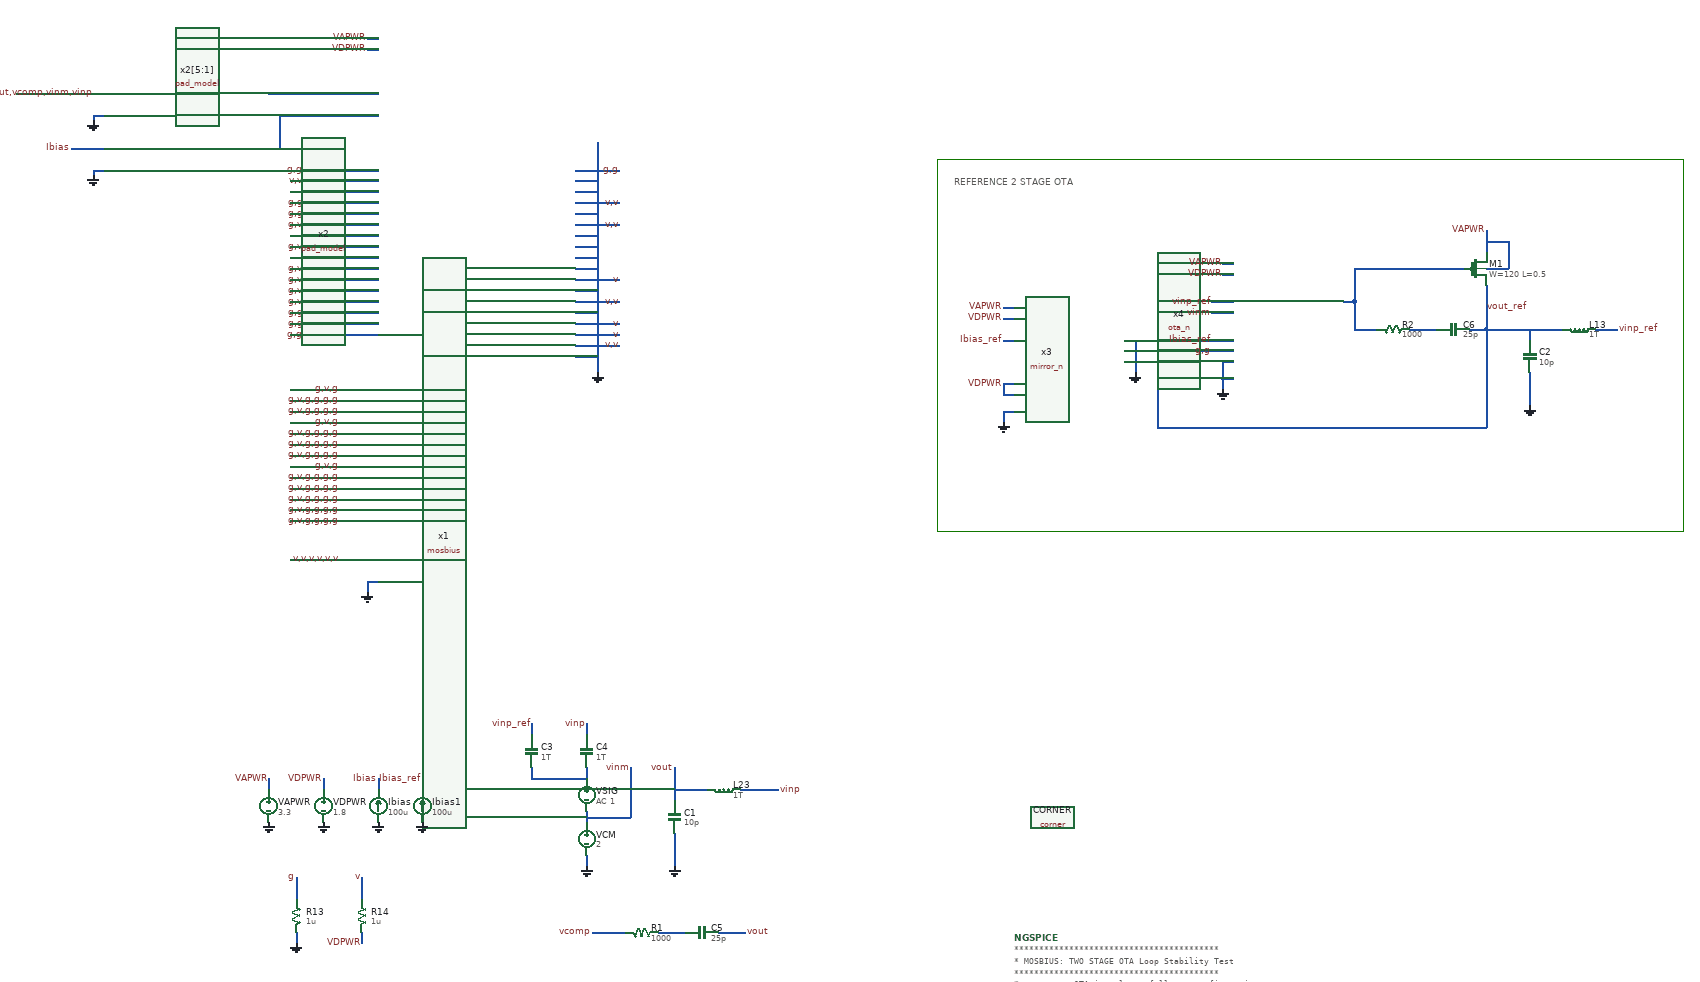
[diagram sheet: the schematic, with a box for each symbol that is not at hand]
v {xschem version=3.1.0 file_version=1.2
}
G {}
K {}
V {}
S {}
E {}
L 4 1320 -1030 1320 -350 {}
L 4 2680 -1030 2680 -350 {}
L 4 1320 -1030 2680 -1030 {}
L 4 1320 -350 2680 -350 {}
T {REFERENCE 2 STAGE OTA} 1350 -1000 0 0 0.4 0.4 {}
N 100 100 100 120 {
lab=VAPWR}
N 200 100 200 120 {
lab=VDPWR}
N 280 -1230 300 -1230 {
lab=VDPWR}
N 280 -1250 300 -1250 {
lab=VAPWR}
N 280 -260 280 -240 {
lab=GND}
N 280 -260 300 -260 {
lab=GND}
N 300 100 300 120 {
lab=Ibias}
N 660 -890 700 -890 {
lab=GND}
N 660 -870 700 -870 {
lab=GND}
N 660 -850 700 -850 {
lab=GND}
N 660 -830 700 -830 {
lab=GND}
N 680 240 680 260 {
lab=GND}
N 680 160 680 180 {
lab=vinm}
N 680 80 680 100 {
lab=#net1}
N 840 80 840 140 {
lab=vout}
N 840 200 840 260 {
lab=GND}
N 680 170 760 170 {
lab=vinm}
N 760 80 760 170 {
lab=vinm}
N 840 120 900 120 {
lab=vout}
N 960 120 1000 120 {
lab=vinp}
N 660 -1010 740 -1010 {
lab=g,g}
N 660 -990 700 -990 {
lab=GND}
N 150 380 150 400 {
lab=GND}
N 150 280 150 320 {
lab=g}
N 270 280 270 320 {
lab=v}
N 270 380 270 400 {
lab=VDPWR}
N 140 -370 300 -370 {
lab=g,v,g,g,g,g}
N 140 -390 300 -390 {
lab=g,v,g,g,g,g}
N 140 -410 300 -410 {
lab=g,v,g,g,g,g}
N 140 -430 300 -430 {
lab=g,v,g,g,g,g}
N 140 -450 300 -450 {
lab=g,v,g,g,g,g}
N 140 -470 300 -470 {
lab=g,v,g}
N 140 -490 300 -490 {
lab=g,v,g,g,g,g}
N 140 -510 300 -510 {
lab=g,v,g,g,g,g}
N 140 -530 300 -530 {
lab=g,v,g,g,g,g}
N 140 -550 300 -550 {
lab=g,v,g}
N 140 -570 300 -570 {
lab=g,v,g,g,g,g}
N 140 -590 300 -590 {
lab=g,v,g,g,g,g}
N 140 -610 300 -610 {
lab=g,v,g}
N 140 -710 300 -710 {
lab=g,g,g,g,g,g}
N 140 -730 300 -730 {
lab=g,g,g,v,g,g}
N 140 -750 300 -750 {
lab=g,g,v,g,g,g}
N 140 -770 300 -770 {
lab=g,v,g,g,g,g}
N 140 -790 300 -790 {
lab=g,v,g,g,g,g}
N 140 -810 300 -810 {
lab=g,v,g,g,g,g}
N 140 -830 300 -830 {
lab=g,v,g,g,g,g}
N 140 -870 300 -870 {
lab=g,v,g,g,g,g}
N 140 -910 300 -910 {
lab=g,v,g,g,g,g}
N 140 -930 300 -930 {
lab=g,g,v,g,g,g}
N 140 -1010 300 -1010 {
lab=g,g,g,g,g,g}
N 140 -850 300 -850 {
lab=g,g,v}
N 140 -890 300 -890 {
lab=g,g,v}
N 140 -300 300 -300 {
lab=v,v,v,v,v,v}
N 140 -990 300 -990 {
lab=v,v,g,g,g,g}
N 140 -970 300 -970 {
lab=g,g,v}
N 140 -950 300 -950 {
lab=g,g,g,v,g,g}
N 1840 -820 1860 -820 {
lab=VDPWR}
N 1840 -840 1860 -840 {
lab=VAPWR}
N 1840 -630 1840 -610 {
lab=GND}
N 1840 -630 1860 -630 {
lab=GND}
N 1440 -740 1460 -740 {
lab=VDPWR}
N 1440 -760 1460 -760 {
lab=VAPWR}
N 1440 -570 1440 -550 {
lab=GND}
N 1440 -570 1460 -570 {
lab=GND}
N 1440 -600 1460 -600 {
lab=VDPWR}
N 1440 -620 1460 -620 {
lab=VDPWR}
N 1440 -620 1440 -600 {
lab=VDPWR}
N 1660 -660 1680 -660 {
lab=GND}
N 380 100 380 120 {
lab=Ibias_ref}
N 1440 -700 1460 -700 {
lab=Ibias_ref}
N 1840 -660 1860 -660 {
lab=GND}
N 1840 -660 1840 -630 {
lab=GND}
N 1800 -680 1860 -680 {
lab=g,g}
N 1820 -770 1860 -770 {
lab=vinp_ref}
N 1820 -750 1860 -750 {
lab=vinm}
N 2400 -640 2400 -580 {
lab=GND}
N 2520 -720 2560 -720 {
lab=vinp_ref}
N 1800 -700 1860 -700 {
lab=Ibias_ref}
N -360 -1150 -200 -1150 {
lab=g,vout,vcomp,vinm,vinp}
N 100 -1150 300 -1150 {
lab=#net2}
N -260 -1050 -200 -1050 {
lab=Ibias}
N 100 -1050 120 -1050 {
lab=#net3}
N 120 -1110 120 -1050 {
lab=#net3}
N 120 -1110 300 -1110 {
lab=#net3}
N -220 -1010 -220 -1000 {
lab=GND}
N -220 -1010 -200 -1010 {
lab=GND}
N -220 -1110 -220 -1100 {
lab=GND}
N -220 -1110 -200 -1110 {
lab=GND}
N 1000 120 1030 120 {
lab=vinp}
N 810 380 860 380 {
lab=#net4}
N 920 380 970 380 {
lab=vout}
N 690 380 750 380 {
lab=vcomp}
N 660 -710 740 -710 {
lab=v}
N 680 -0 680 20 {
lab=vinp}
N 1660 -700 1680 -700 {
lab=GND}
N 700 -1060 700 -640 {
lab=GND}
N 660 -910 740 -910 {
lab=v,v}
N 660 -950 740 -950 {
lab=v,v}
N 660 -970 700 -970 {
lab=GND}
N 660 -930 700 -930 {
lab=GND}
N 660 -810 740 -810 {
lab=v}
N 660 -790 700 -790 {
lab=GND}
N 660 -730 740 -730 {
lab=v}
N 660 -690 740 -690 {
lab=v,v}
N 660 -770 740 -770 {
lab=v,v}
N 660 -750 700 -750 {
lab=GND}
N 660 -670 700 -670 {
lab=GND}
N 2240 -830 2280 -830 {
lab=#net5}
N 1680 -700 1680 -640 {
lab=GND}
N 1660 -680 1720 -680 {
lab=vout_ref}
N 1720 -680 1720 -540 {
lab=vout_ref}
N 1720 -540 2220 -540 {
lab=vout_ref}
N 2320 -900 2320 -860 {
lab=VAPWR}
N 2320 -830 2360 -830 {
lab=VAPWR}
N 2360 -880 2360 -830 {
lab=VAPWR}
N 2320 -880 2360 -880 {
lab=VAPWR}
N 2400 -720 2400 -700 {
lab=vout_ref}
N 580 100 680 100 {
lab=#net1}
N 580 80 580 100 {
lab=#net1}
N 580 0 580 20 {
lab=vinp_ref}
N 2180 -720 2230 -720 {
lab=#net6}
N 2320 -800 2320 -720 {
lab=vout_ref}
N 2320 -720 2460 -720 {
lab=vout_ref}
N 2060 -770 2080 -770 {
lab=#net5}
N 2080 -830 2080 -770 {
lab=#net5}
N 2080 -830 2240 -830 {
lab=#net5}
N 2220 -540 2320 -540 {
lab=vout_ref}
N 2320 -720 2320 -540 {
lab=vout_ref}
N 2290 -720 2320 -720 {
lab=vout_ref}
N 2080 -720 2120 -720 {
lab=#net5}
N 2080 -770 2080 -720 {
lab=#net5}
C {mosbius.sym} 300 -240 0 0 {name=x1}
C {devices/vsource.sym} 100 150 0 0 {name=VAPWR value=3.3}
C {devices/gnd.sym} 100 180 0 0 {name=l1 lab=GND}
C {devices/lab_pin.sym} 100 100 1 0 {name=p2 sig_type=std_logic lab=VAPWR}
C {devices/vsource.sym} 200 150 0 0 {name=VDPWR value=1.8}
C {devices/gnd.sym} 200 180 0 0 {name=l2 lab=GND}
C {devices/lab_pin.sym} 200 100 1 0 {name=p3 sig_type=std_logic lab=VDPWR}
C {devices/lab_pin.sym} 280 -1250 0 0 {name=p4 sig_type=std_logic lab=VAPWR}
C {devices/lab_pin.sym} 280 -1230 0 0 {name=p5 sig_type=std_logic lab=VDPWR}
C {devices/gnd.sym} 280 -240 0 0 {name=l3 lab=GND}
C {devices/isource.sym} 300 150 2 1 {name=Ibias value=100u}
C {devices/gnd.sym} 300 180 0 0 {name=l4 lab=GND}
C {devices/lab_pin.sym} 300 100 1 0 {name=p1 sig_type=std_logic lab=Ibias}
C {devices/gnd.sym} 700 -640 0 0 {name=l5 lab=GND}
C {devices/vsource.sym} 680 130 0 0 {name=VSIG value="AC 1"}
C {devices/vsource.sym} 680 210 0 0 {name=VCM value=2}
C {devices/gnd.sym} 680 260 0 0 {name=l9 lab=GND}
C {devices/lab_pin.sym} 680 0 1 0 {name=p10 sig_type=std_logic lab=vinp}
C {devices/capa.sym} 840 170 0 0 {name=C1
m=1
value=10p
footprint=1206
device="ceramic capacitor"}
C {devices/gnd.sym} 840 260 0 0 {name=l19 lab=GND}
C {devices/lab_pin.sym} 760 80 1 0 {name=p28 sig_type=std_logic lab=vinm}
C {devices/ind.sym} 930 120 1 0 {name=L23
m=1
value=1T
footprint=1206
device=inductor}
C {sky130_fd_pr/corner.sym} 1530 170 0 0 {name=CORNER only_toplevel=true corner=tt}
C {devices/code_shown.sym} 1460 390 0 0 {name=NGSPICE only_toplevel=true value=
"
*****************************************
* MOSBIUS: TWO STAGE OTA Loop Stability Test
*****************************************
* two stage-OTA in voltage follower configuration,
* plots bode plot, and calculates bandwidth and phase margin, 
* compared to reference OTA
*****************************************
* try tuning ctrl_otan_tail[1:0] for variable tail current
*****************************************
* BUS1: OTA INP
* BUS2: OTA INM
* BUS3: OTA Compensation
* BUS4: OTA OUT
* BUS5: GND
* BUS6: GND
*****************************************
.control
   save all
   set temp = 27
   ac dec 51 1k 1G
   let vout_mag = mag(v(vout))                 ; loop gain
   let vout_ref_mag = mag(v(vout_ref))         ; loop gain of reference OTA
   let phase = cph(vout)/PI*180-180            ; phase margin
   let phase_ref = cph(vout_ref)/PI*180-180    ; phase margin of reference OTA
   meas ac f_bw WHEN vout_mag=1                ; calc bandwidth
   meas ac f_bw_ref WHEN vout_ref_mag=1        ; calc bandwidth of reference OTA
   meas ac pm FIND phase AT=f_bw               ; calc phase at ugb
   meas ac pm_ref FIND phase_ref AT=f_bw_ref   ; calc phase at ugb or reference OTA
   plot vdb(vout) vdb(vout_ref)               ; plot loop gain
   plot phase phase_ref
.endc
"}
C {devices/gnd.sym} 150 400 0 0 {name=l10 lab=GND}
C {devices/res.sym} 150 350 0 0 {name=R13
value=1u
footprint=1206
device=resistor
m=1}
C {devices/lab_pin.sym} 150 280 0 0 {name=p17 sig_type=std_logic lab=g}
C {devices/res.sym} 270 350 0 0 {name=R14
value=1u
footprint=1206
device=resistor
m=1}
C {devices/lab_pin.sym} 270 400 3 0 {name=p18 sig_type=std_logic lab=VDPWR}
C {devices/lab_pin.sym} 270 280 0 0 {name=p19 sig_type=std_logic lab=v}
C {devices/lab_wire.sym} 230 -450 0 0 {name=p24 sig_type=std_logic lab=g,v,g,g,g,g}
C {devices/lab_wire.sym} 230 -490 0 0 {name=p39 sig_type=std_logic lab=g,v,g,g,g,g}
C {devices/lab_wire.sym} 230 -510 0 0 {name=p40 sig_type=std_logic lab=g,v,g,g,g,g}
C {devices/lab_wire.sym} 230 -530 0 0 {name=p41 sig_type=std_logic lab=g,v,g,g,g,g}
C {devices/lab_wire.sym} 230 -570 0 0 {name=p43 sig_type=std_logic lab=g,v,g,g,g,g}
C {devices/lab_wire.sym} 230 -590 0 0 {name=p44 sig_type=std_logic lab=g,v,g,g,g,g}
C {devices/lab_wire.sym} 230 -610 0 0 {name=p45 sig_type=std_logic lab=g,v,g}
C {devices/lab_wire.sym} 230 -710 0 0 {name=p46 sig_type=std_logic lab=g,g,g,g,g,g}
C {devices/lab_wire.sym} 230 -730 0 0 {name=p47 sig_type=std_logic lab=g,g,g,v,g,g}
C {devices/lab_wire.sym} 230 -750 0 0 {name=p48 sig_type=std_logic lab=g,g,v,g,g,g}
C {devices/lab_wire.sym} 230 -770 0 0 {name=p49 sig_type=std_logic lab=g,v,g,g,g,g}
C {devices/lab_wire.sym} 230 -790 0 0 {name=p50 sig_type=std_logic lab=g,v,g,g,g,g}
C {devices/lab_wire.sym} 230 -810 0 0 {name=p51 sig_type=std_logic lab=g,v,g,g,g,g}
C {devices/lab_wire.sym} 230 -830 0 0 {name=p52 sig_type=std_logic lab=g,v,g,g,g,g}
C {devices/lab_wire.sym} 230 -870 0 0 {name=p53 sig_type=std_logic lab=g,v,g,g,g,g}
C {devices/lab_wire.sym} 230 -910 0 0 {name=p54 sig_type=std_logic lab=g,v,g,g,g,g}
C {devices/lab_wire.sym} 230 -930 0 0 {name=p55 sig_type=std_logic lab=g,g,v,g,g,g}
C {devices/lab_wire.sym} 230 -1010 0 0 {name=p56 sig_type=std_logic lab=g,g,g,g,g,g}
C {devices/lab_wire.sym} 230 -850 0 0 {name=p57 sig_type=std_logic lab=g,g,v}
C {devices/lab_wire.sym} 230 -890 0 0 {name=p58 sig_type=std_logic lab=g,g,v}
C {devices/lab_wire.sym} 230 -300 0 0 {name=p25 sig_type=std_logic lab=v,v,v,v,v,v}
C {devices/lab_wire.sym} 740 -1010 0 0 {name=p14 sig_type=std_logic lab=g,g}
C {devices/lab_wire.sym} 230 -990 0 0 {name=p11 sig_type=std_logic lab=v,v,g,g,g,g}
C {devices/lab_wire.sym} 230 -970 0 0 {name=p15 sig_type=std_logic lab=g,g,v}
C {devices/lab_wire.sym} 230 -950 0 0 {name=p7 sig_type=std_logic lab=g,g,g,v,g,g}
C {devices/lab_pin.sym} 840 80 1 0 {name=p8 sig_type=std_logic lab=vout}
C {ota_n.sym} 1620 -740 0 0 {name=x4}
C {devices/lab_pin.sym} 1840 -840 0 0 {name=p13 sig_type=std_logic lab=VAPWR}
C {devices/lab_pin.sym} 1840 -820 0 0 {name=p23 sig_type=std_logic lab=VDPWR}
C {devices/gnd.sym} 1840 -610 0 0 {name=l7 lab=GND}
C {mirror_n.sym} 1510 -700 0 0 {name=x3}
C {devices/lab_pin.sym} 1440 -760 0 0 {name=p26 sig_type=std_logic lab=VAPWR}
C {devices/lab_pin.sym} 1440 -740 0 0 {name=p29 sig_type=std_logic lab=VDPWR}
C {devices/gnd.sym} 1440 -550 0 0 {name=l8 lab=GND}
C {devices/gnd.sym} 1680 -640 0 0 {name=l11 lab=GND}
C {devices/isource.sym} 380 150 2 1 {name=Ibias1 value=100u}
C {devices/gnd.sym} 380 180 0 0 {name=l12 lab=GND}
C {devices/lab_pin.sym} 380 100 1 0 {name=p30 sig_type=std_logic lab=Ibias_ref}
C {devices/lab_pin.sym} 1440 -700 0 0 {name=p31 sig_type=std_logic lab=Ibias_ref}
C {devices/lab_pin.sym} 1820 -770 2 1 {name=p12 sig_type=std_logic lab=vinp_ref}
C {devices/lab_pin.sym} 1820 -750 2 1 {name=p32 sig_type=std_logic lab=vinm}
C {devices/capa.sym} 2400 -670 0 0 {name=C2
m=1
value=10p
footprint=1206
device="ceramic capacitor"}
C {devices/gnd.sym} 2400 -580 0 0 {name=l6 lab=GND}
C {devices/ind.sym} 2490 -720 1 0 {name=L13
m=1
value=1T
footprint=1206
device=inductor}
C {devices/lab_pin.sym} 2560 -720 2 0 {name=p34 sig_type=std_logic lab=vinp_ref}
C {devices/lab_wire.sym} 1820 -680 0 0 {name=p35 sig_type=std_logic lab=g,g
}
C {devices/lab_wire.sym} 1820 -700 0 0 {name=p36 sig_type=std_logic lab=Ibias_ref}
C {pad_model.sym} -50 -1130 0 0 {name=x2[5:1]}
C {devices/lab_wire.sym} -220 -1150 0 0 {name=p9 sig_type=std_logic lab=g,vout,vcomp,vinm,vinp}
C {pad_model.sym} -50 -1030 0 0 {name=x2}
C {devices/lab_pin.sym} -260 -1050 0 0 {name=p6 sig_type=std_logic lab=Ibias}
C {devices/gnd.sym} -220 -1100 0 0 {name=l14 lab=GND}
C {devices/gnd.sym} -220 -1000 0 0 {name=l15 lab=GND}
C {devices/lab_wire.sym} 230 -550 0 0 {name=p37 sig_type=std_logic lab=g,v,g}
C {devices/lab_wire.sym} 230 -470 0 0 {name=p27 sig_type=std_logic lab=g,v,g}
C {devices/lab_wire.sym} 230 -430 0 0 {name=p16 sig_type=std_logic lab=g,v,g,g,g,g}
C {devices/lab_wire.sym} 230 -410 0 0 {name=p20 sig_type=std_logic lab=g,v,g,g,g,g}
C {devices/lab_wire.sym} 230 -390 0 0 {name=p21 sig_type=std_logic lab=g,v,g,g,g,g}
C {devices/lab_wire.sym} 230 -370 0 0 {name=p22 sig_type=std_logic lab=g,v,g,g,g,g}
C {devices/capa.sym} 680 50 2 0 {name=C4
m=1
value=1T
footprint=1206
device="ceramic capacitor"}
C {devices/lab_pin.sym} 1030 120 2 0 {name=p38 sig_type=std_logic lab=vinp}
C {devices/capa.sym} 890 380 3 1 {name=C5
m=1
value=25p
footprint=1206
device="ceramic capacitor"}
C {devices/res.sym} 780 380 3 1 {name=R1
value=1000
footprint=1206
device=resistor
m=1}
C {devices/lab_pin.sym} 970 380 0 1 {name=p42 sig_type=std_logic lab=vout}
C {devices/lab_pin.sym} 690 380 2 1 {name=p59 sig_type=std_logic lab=vcomp}
C {devices/lab_wire.sym} 740 -710 0 0 {name=p64 sig_type=std_logic lab=v}
C {devices/lab_wire.sym} 740 -950 0 0 {name=p66 sig_type=std_logic lab=v,v}
C {devices/lab_wire.sym} 740 -910 0 0 {name=p67 sig_type=std_logic lab=v,v}
C {devices/lab_wire.sym} 740 -810 0 0 {name=p60 sig_type=std_logic lab=v}
C {devices/lab_wire.sym} 740 -730 0 0 {name=p61 sig_type=std_logic lab=v}
C {devices/lab_wire.sym} 740 -770 0 0 {name=p62 sig_type=std_logic lab=v,v}
C {devices/lab_wire.sym} 740 -690 0 0 {name=p63 sig_type=std_logic lab=v,v}
C {sky130_fd_pr/pfet_g5v0d10v5.sym} 2300 -830 0 0 {name=M1
L=0.5
W=120
nf=16
mult=1
ad="'int((nf+1)/2) * W/nf * 0.29'" 
pd="'2*int((nf+1)/2) * (W/nf + 0.29)'"
as="'int((nf+2)/2) * W/nf * 0.29'" 
ps="'2*int((nf+2)/2) * (W/nf + 0.29)'"
nrd="'0.29 / W'" nrs="'0.29 / W'"
sa=0 sb=0 sd=0
model=pfet_g5v0d10v5
spiceprefix=X
}
C {devices/lab_pin.sym} 1440 -620 0 0 {name=p65 sig_type=std_logic lab=VDPWR}
C {devices/lab_pin.sym} 2320 -900 0 0 {name=p68 sig_type=std_logic lab=VAPWR}
C {devices/capa.sym} 580 50 2 0 {name=C3
m=1
value=1T
footprint=1206
device="ceramic capacitor"}
C {devices/lab_pin.sym} 580 0 1 0 {name=p33 sig_type=std_logic lab=vinp_ref}
C {devices/lab_pin.sym} 2320 -760 2 0 {name=p69 sig_type=std_logic lab=vout_ref}
C {devices/capa.sym} 2260 -720 3 1 {name=C6
m=1
value=25p
footprint=1206
device="ceramic capacitor"}
C {devices/res.sym} 2150 -720 3 1 {name=R2
value=1000
footprint=1206
device=resistor
m=1}
